VERSION 5.8 ;
BUSBITCHARS "[]" ;
DIVIDERCHAR "/" ;
UNITS
    DATABASE MICRONS 2000 ;
END UNITS

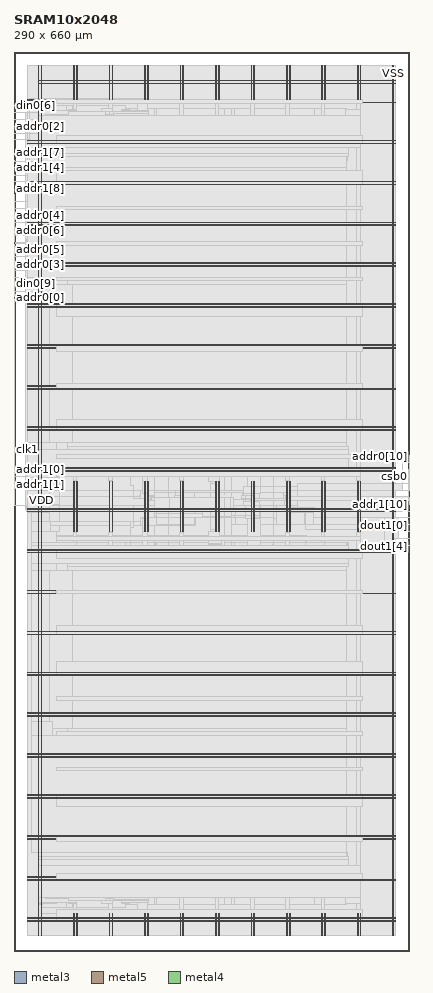
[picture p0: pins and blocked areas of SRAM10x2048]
MACRO SRAM10x2048
  FOREIGN SRAM10x2048 0 0 ;
  CLASS BLOCK ;
  SIZE 290 BY 660 ;
  PIN addr0[0]
    DIRECTION INPUT ;
    USE SIGNAL ;
    PORT
      LAYER metal3 ;
        RECT  0 478.835 0.07 478.905 ;
    END
  END addr0[0]
  PIN addr0[10]
    DIRECTION INPUT ;
    USE SIGNAL ;
    PORT
      LAYER metal3 ;
        RECT  289.93 362.915 290 362.985 ;
    END
  END addr0[10]
  PIN addr0[1]
    DIRECTION INPUT ;
    USE SIGNAL ;
    PORT
      LAYER metal3 ;
        RECT  0 609.875 0.07 609.945 ;
    END
  END addr0[1]
  PIN addr0[2]
    DIRECTION INPUT ;
    USE SIGNAL ;
    PORT
      LAYER metal3 ;
        RECT  0 604.835 0.07 604.905 ;
    END
  END addr0[2]
  PIN addr0[3]
    DIRECTION INPUT ;
    USE SIGNAL ;
    PORT
      LAYER metal3 ;
        RECT  0 509.075 0.07 509.145 ;
    END
  END addr0[3]
  PIN addr0[4]
    DIRECTION INPUT ;
    USE SIGNAL ;
    PORT
      LAYER metal3 ;
        RECT  0 539.315 0.07 539.385 ;
    END
  END addr0[4]
  PIN addr0[5]
    DIRECTION INPUT ;
    USE SIGNAL ;
    PORT
      LAYER metal3 ;
        RECT  0 514.115 0.07 514.185 ;
    END
  END addr0[5]
  PIN addr0[6]
    DIRECTION INPUT ;
    USE SIGNAL ;
    PORT
      LAYER metal3 ;
        RECT  0 534.275 0.07 534.345 ;
    END
  END addr0[6]
  PIN addr0[7]
    DIRECTION INPUT ;
    USE SIGNAL ;
    PORT
      LAYER metal3 ;
        RECT  0 519.155 0.07 519.225 ;
    END
  END addr0[7]
  PIN addr0[8]
    DIRECTION INPUT ;
    USE SIGNAL ;
    PORT
      LAYER metal3 ;
        RECT  0 529.235 0.07 529.305 ;
    END
  END addr0[8]
  PIN addr0[9]
    DIRECTION INPUT ;
    USE SIGNAL ;
    PORT
      LAYER metal3 ;
        RECT  0 524.195 0.07 524.265 ;
    END
  END addr0[9]
  PIN addr1[0]
    DIRECTION INPUT ;
    USE SIGNAL ;
    PORT
      LAYER metal3 ;
        RECT  0 352.835 0.07 352.905 ;
    END
  END addr1[0]
  PIN addr1[10]
    DIRECTION INPUT ;
    USE SIGNAL ;
    PORT
      LAYER metal3 ;
        RECT  289.93 327.635 290 327.705 ;
    END
  END addr1[10]
  PIN addr1[1]
    DIRECTION INPUT ;
    USE SIGNAL ;
    PORT
      LAYER metal3 ;
        RECT  0 347.795 0.07 347.865 ;
    END
  END addr1[1]
  PIN addr1[2]
    DIRECTION INPUT ;
    USE SIGNAL ;
    PORT
      LAYER metal3 ;
        RECT  0 342.755 0.07 342.825 ;
    END
  END addr1[2]
  PIN addr1[3]
    DIRECTION INPUT ;
    USE SIGNAL ;
    PORT
      LAYER metal3 ;
        RECT  0 549.395 0.07 549.465 ;
    END
  END addr1[3]
  PIN addr1[4]
    DIRECTION INPUT ;
    USE SIGNAL ;
    PORT
      LAYER metal3 ;
        RECT  0 574.595 0.07 574.665 ;
    END
  END addr1[4]
  PIN addr1[5]
    DIRECTION INPUT ;
    USE SIGNAL ;
    PORT
      LAYER metal3 ;
        RECT  0 569.555 0.07 569.625 ;
    END
  END addr1[5]
  PIN addr1[6]
    DIRECTION INPUT ;
    USE SIGNAL ;
    PORT
      LAYER metal3 ;
        RECT  0 564.515 0.07 564.585 ;
    END
  END addr1[6]
  PIN addr1[7]
    DIRECTION INPUT ;
    USE SIGNAL ;
    PORT
      LAYER metal3 ;
        RECT  0 579.635 0.07 579.705 ;
    END
  END addr1[7]
  PIN addr1[8]
    DIRECTION INPUT ;
    USE SIGNAL ;
    PORT
      LAYER metal3 ;
        RECT  0 559.475 0.07 559.545 ;
    END
  END addr1[8]
  PIN addr1[9]
    DIRECTION INPUT ;
    USE SIGNAL ;
    PORT
      LAYER metal3 ;
        RECT  0 584.675 0.07 584.745 ;
    END
  END addr1[9]
  PIN clk0
    DIRECTION INPUT ;
    USE SIGNAL ;
    PORT
      LAYER metal3 ;
        RECT  0 554.435 0.07 554.505 ;
    END
  END clk0
  PIN clk1
    DIRECTION INPUT ;
    USE SIGNAL ;
    PORT
      LAYER metal3 ;
        RECT  0 367.955 0.07 368.025 ;
    END
  END clk1
  PIN csb0
    DIRECTION INPUT ;
    USE SIGNAL ;
    PORT
      LAYER metal3 ;
        RECT  289.93 347.795 290 347.865 ;
    END
  END csb0
  PIN csb1
    DIRECTION INPUT ;
    USE SIGNAL ;
    PORT
      LAYER metal3 ;
        RECT  289.93 332.675 290 332.745 ;
    END
  END csb1
  PIN din0[0]
    DIRECTION INPUT ;
    USE SIGNAL ;
    PORT
      LAYER metal3 ;
        RECT  0 599.795 0.07 599.865 ;
    END
  END din0[0]
  PIN din0[1]
    DIRECTION INPUT ;
    USE SIGNAL ;
    PORT
      LAYER metal3 ;
        RECT  0 594.755 0.07 594.825 ;
    END
  END din0[1]
  PIN din0[2]
    DIRECTION INPUT ;
    USE SIGNAL ;
    PORT
      LAYER metal3 ;
        RECT  0 544.355 0.07 544.425 ;
    END
  END din0[2]
  PIN din0[3]
    DIRECTION INPUT ;
    USE SIGNAL ;
    PORT
      LAYER metal3 ;
        RECT  0 614.915 0.07 614.985 ;
    END
  END din0[3]
  PIN din0[4]
    DIRECTION INPUT ;
    USE SIGNAL ;
    PORT
      LAYER metal3 ;
        RECT  0 504.035 0.07 504.105 ;
    END
  END din0[4]
  PIN din0[5]
    DIRECTION INPUT ;
    USE SIGNAL ;
    PORT
      LAYER metal3 ;
        RECT  0 498.995 0.07 499.065 ;
    END
  END din0[5]
  PIN din0[6]
    DIRECTION INPUT ;
    USE SIGNAL ;
    PORT
      LAYER metal3 ;
        RECT  0 619.955 0.07 620.025 ;
    END
  END din0[6]
  PIN din0[7]
    DIRECTION INPUT ;
    USE SIGNAL ;
    PORT
      LAYER metal3 ;
        RECT  0 493.955 0.07 494.025 ;
    END
  END din0[7]
  PIN din0[8]
    DIRECTION INPUT ;
    USE SIGNAL ;
    PORT
      LAYER metal3 ;
        RECT  0 488.915 0.07 488.985 ;
    END
  END din0[8]
  PIN din0[9]
    DIRECTION INPUT ;
    USE SIGNAL ;
    PORT
      LAYER metal3 ;
        RECT  0 483.875 0.07 483.945 ;
    END
  END din0[9]
  PIN dout1[0]
    DIRECTION OUTPUT ;
    USE SIGNAL ;
    PORT
      LAYER metal3 ;
        RECT  289.93 317.555 290 317.625 ;
    END
  END dout1[0]
  PIN dout1[1]
    DIRECTION OUTPUT ;
    USE SIGNAL ;
    PORT
      LAYER metal3 ;
        RECT  289.93 312.515 290 312.585 ;
    END
  END dout1[1]
  PIN dout1[2]
    DIRECTION OUTPUT ;
    USE SIGNAL ;
    PORT
      LAYER metal3 ;
        RECT  289.93 357.875 290 357.945 ;
    END
  END dout1[2]
  PIN dout1[3]
    DIRECTION OUTPUT ;
    USE SIGNAL ;
    PORT
      LAYER metal3 ;
        RECT  289.93 337.715 290 337.785 ;
    END
  END dout1[3]
  PIN dout1[4]
    DIRECTION OUTPUT ;
    USE SIGNAL ;
    PORT
      LAYER metal3 ;
        RECT  289.93 302.435 290 302.505 ;
    END
  END dout1[4]
  PIN dout1[5]
    DIRECTION OUTPUT ;
    USE SIGNAL ;
    PORT
      LAYER metal3 ;
        RECT  289.93 352.835 290 352.905 ;
    END
  END dout1[5]
  PIN dout1[6]
    DIRECTION OUTPUT ;
    USE SIGNAL ;
    PORT
      LAYER metal3 ;
        RECT  289.93 297.395 290 297.465 ;
    END
  END dout1[6]
  PIN dout1[7]
    DIRECTION OUTPUT ;
    USE SIGNAL ;
    PORT
      LAYER metal3 ;
        RECT  289.93 342.755 290 342.825 ;
    END
  END dout1[7]
  PIN dout1[8]
    DIRECTION OUTPUT ;
    USE SIGNAL ;
    PORT
      LAYER metal3 ;
        RECT  289.93 307.475 290 307.545 ;
    END
  END dout1[8]
  PIN dout1[9]
    DIRECTION OUTPUT ;
    USE SIGNAL ;
    PORT
      LAYER metal3 ;
        RECT  289.93 322.595 290 322.665 ;
    END
  END dout1[9]
  PIN VSS
    DIRECTION INOUT ;
    USE GROUND ;
    PORT
      LAYER metal5 ;
        RECT  17.82 638.22 279.87 638.72 ;
        RECT  256.47 621.95 279.87 622.45 ;
        RECT  256.47 441.95 279.87 442.45 ;
        RECT  256.47 261.95 279.87 262.45 ;
        RECT  256.47 81.95 279.87 82.45 ;
        RECT  10.07 621.95 30.62 622.45 ;
        RECT  10.07 591.95 279.87 592.45 ;
        RECT  10.07 561.95 279.87 562.45 ;
        RECT  10.07 531.95 279.87 532.45 ;
        RECT  10.07 501.95 279.87 502.45 ;
        RECT  10.07 471.95 279.87 472.45 ;
        RECT  10.07 441.95 30.62 442.45 ;
        RECT  10.07 411.95 279.87 412.45 ;
        RECT  10.07 381.95 279.87 382.45 ;
        RECT  10.07 351.95 279.87 352.45 ;
        RECT  10.07 321.95 279.87 322.45 ;
        RECT  10.07 291.95 279.87 292.45 ;
        RECT  10.07 261.95 30.62 262.45 ;
        RECT  10.07 231.95 279.87 232.45 ;
        RECT  10.07 201.95 279.87 202.45 ;
        RECT  10.07 171.95 279.87 172.45 ;
        RECT  10.07 141.95 279.87 142.45 ;
        RECT  10.07 111.95 279.87 112.45 ;
        RECT  10.07 81.95 30.62 82.45 ;
        RECT  10.07 51.95 279.87 52.45 ;
        RECT  10.07 21.95 279.87 22.45 ;
      LAYER metal4 ;
        RECT  277.82 11.13 278.32 649.67 ;
        RECT  251.82 624.63 252.32 649.67 ;
        RECT  251.82 307.46 252.32 344.66 ;
        RECT  251.82 11.13 252.32 27.49 ;
        RECT  225.82 624.63 226.32 649.67 ;
        RECT  225.82 307.46 226.32 344.66 ;
        RECT  225.82 11.13 226.32 27.49 ;
        RECT  199.82 624.63 200.32 649.67 ;
        RECT  199.82 307.46 200.32 344.66 ;
        RECT  199.82 11.13 200.32 27.49 ;
        RECT  173.82 624.63 174.32 649.67 ;
        RECT  173.82 307.46 174.32 344.66 ;
        RECT  173.82 11.13 174.32 27.49 ;
        RECT  147.82 624.63 148.32 649.67 ;
        RECT  147.82 307.46 148.32 344.66 ;
        RECT  147.82 11.13 148.32 27.49 ;
        RECT  121.82 624.63 122.32 649.67 ;
        RECT  121.82 307.46 122.32 344.66 ;
        RECT  121.82 11.13 122.32 27.49 ;
        RECT  95.82 624.63 96.32 649.67 ;
        RECT  95.82 307.46 96.32 344.66 ;
        RECT  95.82 11.13 96.32 27.49 ;
        RECT  69.82 624.63 70.32 649.67 ;
        RECT  69.82 307.46 70.32 344.66 ;
        RECT  69.82 11.13 70.32 27.49 ;
        RECT  43.82 624.63 44.32 649.67 ;
        RECT  43.82 307.46 44.32 344.66 ;
        RECT  43.82 11.13 44.32 27.49 ;
        RECT  17.82 11.13 18.32 649.67 ;
    END
  END VSS
  PIN VDD
    DIRECTION INOUT ;
    USE POWER ;
    PORT
      LAYER metal5 ;
        RECT  17.82 635.98 279.87 636.48 ;
        RECT  10.07 624.05 30.62 624.55 ;
        RECT  10.07 594.05 279.87 594.55 ;
        RECT  10.07 564.05 279.87 564.55 ;
        RECT  10.07 534.05 279.87 534.55 ;
        RECT  10.07 504.05 279.87 504.55 ;
        RECT  10.07 474.05 279.87 474.55 ;
        RECT  10.07 444.05 279.87 444.55 ;
        RECT  10.07 414.05 30.62 414.55 ;
        RECT  10.07 384.05 279.87 384.55 ;
        RECT  10.07 354.05 279.87 354.55 ;
        RECT  10.07 324.05 279.87 324.55 ;
        RECT  10.07 294.05 279.87 294.55 ;
        RECT  10.07 264.05 30.62 264.55 ;
        RECT  10.07 234.05 279.87 234.55 ;
        RECT  10.07 204.05 279.87 204.55 ;
        RECT  10.07 174.05 279.87 174.55 ;
        RECT  10.07 144.05 279.87 144.55 ;
        RECT  10.07 114.05 279.87 114.55 ;
        RECT  10.07 84.05 279.87 84.55 ;
        RECT  10.07 54.05 30.62 54.55 ;
        RECT  10.07 24.05 279.87 24.55 ;
      LAYER metal4 ;
        RECT  253.92 624.42 254.42 649.64 ;
        RECT  253.92 307.49 254.42 344.63 ;
        RECT  253.92 11.16 254.42 27.7 ;
        RECT  227.92 624.42 228.42 649.64 ;
        RECT  227.92 307.49 228.42 344.63 ;
        RECT  227.92 11.16 228.42 27.7 ;
        RECT  201.92 624.42 202.42 649.64 ;
        RECT  201.92 307.49 202.42 344.63 ;
        RECT  201.92 11.16 202.42 27.7 ;
        RECT  175.92 624.42 176.42 649.64 ;
        RECT  175.92 307.49 176.42 344.63 ;
        RECT  175.92 11.16 176.42 27.7 ;
        RECT  149.92 624.42 150.42 649.64 ;
        RECT  149.92 307.49 150.42 344.63 ;
        RECT  149.92 11.16 150.42 27.7 ;
        RECT  123.92 624.42 124.42 649.64 ;
        RECT  123.92 307.49 124.42 344.63 ;
        RECT  123.92 11.16 124.42 27.7 ;
        RECT  97.92 624.42 98.42 649.64 ;
        RECT  97.92 307.49 98.42 344.63 ;
        RECT  97.92 11.16 98.42 27.7 ;
        RECT  71.92 624.42 72.42 649.64 ;
        RECT  71.92 307.49 72.42 344.63 ;
        RECT  71.92 11.16 72.42 27.7 ;
        RECT  45.92 624.42 46.42 649.64 ;
        RECT  45.92 307.49 46.42 344.63 ;
        RECT  45.92 11.16 46.42 27.7 ;
        RECT  19.92 11.16 20.42 649.64 ;
    END
  END VDD
  OBS
    LAYER metal1 ;
     RECT  10.07 11.115 279.87 649.685 ;
    LAYER metal2 ;
     RECT  17.84 11.13 18.3 12.53 ;
     RECT  43.84 11.13 44.3 12.53 ;
     RECT  69.84 11.13 70.3 12.53 ;
     RECT  95.84 11.13 96.3 12.53 ;
     RECT  121.84 11.13 122.3 12.53 ;
     RECT  147.84 11.13 148.3 12.53 ;
     RECT  173.84 11.13 174.3 12.53 ;
     RECT  199.84 11.13 200.3 12.53 ;
     RECT  225.84 11.13 226.3 12.53 ;
     RECT  251.84 11.13 252.3 12.53 ;
     RECT  43.84 12.53 46.4 26.67 ;
     RECT  69.84 12.53 72.4 26.67 ;
     RECT  95.84 12.53 98.4 26.67 ;
     RECT  121.84 12.53 124.4 26.67 ;
     RECT  147.84 12.53 150.4 26.67 ;
     RECT  173.84 12.53 176.4 26.67 ;
     RECT  199.84 12.53 202.4 26.67 ;
     RECT  225.84 12.53 228.4 26.67 ;
     RECT  251.84 12.53 254.4 26.67 ;
     RECT  43.84 26.67 45.99 28.21 ;
     RECT  69.84 26.67 71.99 28.21 ;
     RECT  95.84 26.67 97.99 28.21 ;
     RECT  121.84 26.67 123.99 28.21 ;
     RECT  147.84 26.67 149.99 28.21 ;
     RECT  173.84 26.67 175.99 28.21 ;
     RECT  199.84 26.67 201.99 28.21 ;
     RECT  225.84 26.67 227.99 28.21 ;
     RECT  251.84 26.67 253.99 28.21 ;
     RECT  244.4 35.42 244.47 36.96 ;
     RECT  43.43 28.21 45.99 39.28 ;
     RECT  69.43 28.21 71.99 39.28 ;
     RECT  95.43 28.21 97.99 39.28 ;
     RECT  121.43 28.21 123.99 39.28 ;
     RECT  147.43 28.21 149.99 39.28 ;
     RECT  173.43 28.21 175.99 39.28 ;
     RECT  199.43 28.21 201.99 39.28 ;
     RECT  225.43 28.21 227.99 39.28 ;
     RECT  244.21 36.96 244.47 39.28 ;
     RECT  43.385 39.28 244.47 60.13 ;
     RECT  17.84 12.53 20.4 62.58 ;
     RECT  17.84 62.58 22.93 68.6 ;
     RECT  43.385 60.13 244.28 72.1 ;
     RECT  43.385 72.1 244.05 297.49 ;
     RECT  43.43 297.49 45.99 305.55 ;
     RECT  69.43 297.49 71.99 305.55 ;
     RECT  95.43 297.49 97.99 305.55 ;
     RECT  121.43 297.49 123.99 305.55 ;
     RECT  173.43 297.49 175.99 305.55 ;
     RECT  199.43 297.49 201.99 305.55 ;
     RECT  225.43 297.49 227.99 305.55 ;
     RECT  251.43 28.21 253.99 305.55 ;
     RECT  147.43 297.49 149.99 307.72 ;
     RECT  284.87 307.44 284.94 309.26 ;
     RECT  43.84 305.55 45.99 309.33 ;
     RECT  69.84 305.55 71.99 309.33 ;
     RECT  95.84 305.55 97.99 309.33 ;
     RECT  121.84 305.55 123.99 309.33 ;
     RECT  144.08 307.72 149.99 309.33 ;
     RECT  173.84 305.55 175.99 309.33 ;
     RECT  199.84 305.55 201.99 309.33 ;
     RECT  225.84 305.55 227.99 309.33 ;
     RECT  251.84 305.55 253.99 309.33 ;
     RECT  159.47 297.49 159.54 312.48 ;
     RECT  103.04 297.49 103.11 315.14 ;
     RECT  95.84 309.33 98.4 316.82 ;
     RECT  173.84 309.33 176.4 316.82 ;
     RECT  192.72 315.14 192.79 316.82 ;
     RECT  92.78 316.82 98.4 318.08 ;
     RECT  121.84 309.33 124.4 318.08 ;
     RECT  190.25 316.82 192.79 318.08 ;
     RECT  33.5 307.86 33.57 318.22 ;
     RECT  121.84 318.08 124.58 318.22 ;
     RECT  103.04 315.14 104.44 318.5 ;
     RECT  132.68 312.34 132.75 318.5 ;
     RECT  199.84 309.33 202.4 318.5 ;
     RECT  33.12 318.5 33.19 318.64 ;
     RECT  190.25 318.08 192.41 318.64 ;
     RECT  132.49 318.5 132.94 318.78 ;
     RECT  190.25 318.64 191.84 318.92 ;
     RECT  103.04 318.5 104.63 320.88 ;
     RECT  190.25 318.92 191.08 320.88 ;
     RECT  214 309.12 214.07 320.88 ;
     RECT  219.7 320.74 219.77 321.16 ;
     RECT  212.86 321.16 213.69 321.3 ;
     RECT  10.7 321.3 11.72 321.335 ;
     RECT  213.05 321.3 213.69 321.44 ;
     RECT  213.05 321.44 213.12 321.72 ;
     RECT  138 320.74 138.07 322.28 ;
     RECT  159.47 312.48 162.2 322.28 ;
     RECT  9.75 321.335 11.72 322.56 ;
     RECT  218.94 321.16 219.77 322.56 ;
     RECT  159.47 322.28 161.82 322.7 ;
     RECT  159.47 322.7 161.25 323.54 ;
     RECT  191.01 320.88 191.08 323.68 ;
     RECT  199.84 318.5 205.33 323.68 ;
     RECT  154.34 301.98 154.41 323.82 ;
     RECT  9.56 322.56 12.67 324.1 ;
     RECT  158.9 323.54 161.25 324.1 ;
     RECT  8.61 324.1 13.62 324.24 ;
     RECT  87.65 310.52 87.72 324.24 ;
     RECT  157.76 324.1 161.25 324.38 ;
     RECT  218.94 322.56 220.15 325.08 ;
     RECT  8.61 324.24 12.67 325.5 ;
     RECT  218.94 325.08 219.77 325.5 ;
     RECT  8.61 325.5 11.72 325.64 ;
     RECT  198.42 323.68 205.33 326.34 ;
     RECT  17.84 68.6 20.4 326.48 ;
     RECT  169.73 316.82 169.8 326.48 ;
     RECT  17.84 326.48 21.98 326.62 ;
     RECT  17.84 326.62 21.22 327.04 ;
     RECT  17.84 327.04 20.65 327.32 ;
     RECT  103.04 320.88 104.25 329.28 ;
     RECT  173.84 316.82 180.06 329.7 ;
     RECT  289.81 327.6 289.88 330.82 ;
     RECT  95.84 318.08 98.4 330.96 ;
     RECT  167.83 329.14 167.9 330.96 ;
     RECT  121.84 318.22 124.4 331.1 ;
     RECT  167.07 330.96 167.9 331.1 ;
     RECT  173.34 329.7 180.06 331.1 ;
     RECT  104.18 329.28 104.25 331.24 ;
     RECT  198.42 326.34 207.61 331.52 ;
     RECT  118.05 331.1 124.4 331.94 ;
     RECT  198.42 331.52 207.99 331.94 ;
     RECT  137.81 322.56 137.88 332.08 ;
     RECT  167.07 331.1 180.06 332.08 ;
     RECT  197.66 331.94 207.99 332.08 ;
     RECT  95.84 330.96 99.5 332.22 ;
     RECT  157.95 324.38 161.25 332.22 ;
     RECT  159.47 332.22 161.25 332.64 ;
     RECT  92.78 332.22 99.5 332.78 ;
     RECT  92.21 332.78 99.5 333.2 ;
     RECT  33.12 333.76 33.19 333.9 ;
     RECT  92.21 333.2 103.3 333.9 ;
     RECT  117.86 331.94 124.4 333.9 ;
     RECT  167.07 332.08 169.8 333.9 ;
     RECT  197.66 332.08 202.4 333.9 ;
     RECT  118.43 333.9 124.4 334.18 ;
     RECT  92.78 333.9 98.4 335.3 ;
     RECT  113.3 316.82 113.37 335.3 ;
     RECT  167.26 333.9 169.8 335.3 ;
     RECT  173.84 332.08 180.06 335.3 ;
     RECT  190.25 325.36 190.32 335.3 ;
     RECT  103.04 333.9 103.3 336.42 ;
     RECT  167.26 335.3 167.33 336.42 ;
     RECT  132.49 318.78 132.56 336.56 ;
     RECT  154.34 335.04 154.6 336.56 ;
     RECT  197.85 333.9 202.4 336.56 ;
     RECT  289.43 333.48 289.5 337.54 ;
     RECT  118.43 334.18 124.58 337.68 ;
     RECT  118.43 337.68 124.4 337.96 ;
     RECT  173.84 335.3 179.49 337.96 ;
     RECT  87.65 332.08 87.72 341.6 ;
     RECT  207.92 332.08 207.99 342.86 ;
     RECT  43.84 309.33 46.4 343.07 ;
     RECT  69.84 309.33 72.4 343.07 ;
     RECT  95.84 335.3 98.4 343.07 ;
     RECT  121.84 337.96 124.4 343.07 ;
     RECT  144.08 309.33 150.4 343.07 ;
     RECT  173.84 337.96 176.4 343.07 ;
     RECT  199.84 336.56 202.4 343.07 ;
     RECT  225.84 309.33 228.4 343.07 ;
     RECT  251.84 309.33 254.4 343.07 ;
     RECT  144.08 343.07 149.99 344.4 ;
     RECT  43.84 343.07 45.99 346.57 ;
     RECT  69.84 343.07 71.99 346.57 ;
     RECT  95.84 343.07 97.99 346.57 ;
     RECT  121.84 343.07 123.99 346.57 ;
     RECT  173.84 343.07 175.99 346.57 ;
     RECT  199.84 343.07 201.99 346.57 ;
     RECT  225.84 343.07 227.99 346.57 ;
     RECT  251.84 343.07 253.99 346.57 ;
     RECT  33.5 334.18 33.57 347.62 ;
     RECT  154.34 336.56 154.41 350.14 ;
     RECT  289.43 337.54 289.88 352.94 ;
     RECT  43.43 346.57 45.99 354.63 ;
     RECT  69.43 346.57 71.99 354.63 ;
     RECT  95.43 346.57 97.99 354.63 ;
     RECT  103.04 336.42 103.11 354.63 ;
     RECT  121.43 346.57 123.99 354.63 ;
     RECT  147.43 344.4 149.99 354.63 ;
     RECT  159.47 332.64 159.54 354.63 ;
     RECT  173.43 346.57 175.99 354.63 ;
     RECT  199.43 346.57 201.99 354.63 ;
     RECT  225.43 346.57 227.99 354.63 ;
     RECT  284.87 340.48 284.94 357.98 ;
     RECT  289.81 352.94 289.88 363.02 ;
     RECT  17.84 327.32 20.4 481.46 ;
     RECT  17.84 481.46 21.22 488.74 ;
     RECT  8.61 325.64 11.34 527.1 ;
     RECT  8.61 527.1 11.53 529.06 ;
     RECT  8.61 529.06 11.34 537.32 ;
     RECT  8.61 537.32 11.53 539.28 ;
     RECT  17.84 488.74 20.4 578.48 ;
     RECT  43.385 354.63 244.05 580.02 ;
     RECT  17.84 578.48 21.22 584.08 ;
     RECT  17.84 584.08 21.41 588.84 ;
     RECT  43.385 580.02 244.28 591.99 ;
     RECT  8.61 539.28 11.34 603.12 ;
     RECT  8.61 603.12 11.53 604.66 ;
     RECT  8.61 604.66 11.34 612.64 ;
     RECT  43.385 591.99 244.47 612.84 ;
     RECT  10.13 612.64 11.53 614.88 ;
     RECT  10.13 614.88 11.34 615.02 ;
     RECT  244.21 612.84 244.47 615.16 ;
     RECT  10.13 615.02 11.15 616.7 ;
     RECT  244.4 615.16 244.47 616.7 ;
     RECT  10.51 616.7 11.15 617.26 ;
     RECT  10.7 617.26 11.15 621.18 ;
     RECT  10.13 621.18 11.15 622.3 ;
     RECT  10.51 622.3 11.15 622.86 ;
     RECT  10.7 622.86 11.15 623.84 ;
     RECT  43.43 612.84 45.99 623.91 ;
     RECT  69.43 612.84 71.99 623.91 ;
     RECT  95.43 612.84 97.99 623.91 ;
     RECT  121.43 612.84 123.99 623.91 ;
     RECT  147.43 612.84 149.99 623.91 ;
     RECT  173.43 612.84 175.99 623.91 ;
     RECT  199.43 612.84 201.99 623.91 ;
     RECT  225.43 612.84 227.99 623.91 ;
     RECT  251.43 346.57 253.99 623.91 ;
     RECT  11.08 623.84 11.15 624.96 ;
     RECT  43.84 623.91 45.99 625.73 ;
     RECT  69.84 623.91 71.99 625.73 ;
     RECT  95.84 623.91 97.99 625.73 ;
     RECT  121.84 623.91 123.99 625.73 ;
     RECT  147.84 623.91 149.99 625.73 ;
     RECT  173.84 623.91 175.99 625.73 ;
     RECT  199.84 623.91 201.99 625.73 ;
     RECT  225.84 623.91 227.99 625.73 ;
     RECT  251.84 623.91 253.99 625.73 ;
     RECT  17.84 588.84 20.4 648.27 ;
     RECT  43.84 625.73 46.4 648.27 ;
     RECT  69.84 625.73 72.4 648.27 ;
     RECT  95.84 625.73 98.4 648.27 ;
     RECT  121.84 625.73 124.4 648.27 ;
     RECT  147.84 625.73 150.4 648.27 ;
     RECT  173.84 625.73 176.4 648.27 ;
     RECT  199.84 625.73 202.4 648.27 ;
     RECT  225.84 625.73 228.4 648.27 ;
     RECT  251.84 625.73 254.4 648.27 ;
     RECT  17.84 648.27 18.3 649.67 ;
     RECT  43.84 648.27 44.3 649.67 ;
     RECT  69.84 648.27 70.3 649.67 ;
     RECT  95.84 648.27 96.3 649.67 ;
     RECT  121.84 648.27 122.3 649.67 ;
     RECT  147.84 648.27 148.3 649.67 ;
     RECT  173.84 648.27 174.3 649.67 ;
     RECT  199.84 648.27 200.3 649.67 ;
     RECT  225.84 648.27 226.3 649.67 ;
     RECT  251.84 648.27 252.3 649.67 ;
     RECT  277.84 11.13 278.3 649.67 ;
    LAYER metal3 ;
     RECT  0 489.055 0.035 489.825 ;
     RECT  0 559.615 0.035 559.825 ;
     RECT  0 568.575 0.035 569.485 ;
     RECT  0 579.215 0.035 579.565 ;
     RECT  0 584.255 0.035 584.605 ;
     RECT  0.035 524.195 0.06 524.265 ;
     RECT  0.035 488.915 0.13 489.825 ;
     RECT  0.06 524.195 0.13 524.405 ;
     RECT  0.035 559.475 0.13 559.825 ;
     RECT  0.035 568.575 0.13 569.625 ;
     RECT  0.035 579.215 0.13 579.705 ;
     RECT  0.035 584.255 0.13 584.745 ;
     RECT  0.025 554.435 0.165 554.505 ;
     RECT  0.025 326.935 8.575 327.005 ;
     RECT  0.035 609.875 8.575 609.945 ;
     RECT  0.035 614.915 8.575 614.985 ;
     RECT  0.035 604.835 8.765 604.905 ;
     RECT  0.035 529.235 8.955 529.305 ;
     RECT  0.035 514.115 9.335 514.185 ;
     RECT  9.335 514.115 9.475 516.145 ;
     RECT  8.575 324.135 9.525 327.005 ;
     RECT  0.035 519.155 9.525 519.225 ;
     RECT  8.955 529.235 9.525 530.005 ;
     RECT  0.035 534.275 9.525 534.345 ;
     RECT  0.13 489.755 9.86 489.825 ;
     RECT  9.86 489.755 9.93 490.665 ;
     RECT  0.035 544.355 10.045 544.425 ;
     RECT  0.035 539.315 10.095 539.385 ;
     RECT  0.035 619.955 10.095 620.025 ;
     RECT  9.525 322.595 10.105 327.005 ;
     RECT  9.93 490.595 10.235 490.665 ;
     RECT  0.035 493.955 10.235 494.025 ;
     RECT  0.035 509.075 10.235 509.145 ;
     RECT  9.475 515.795 10.235 516.145 ;
     RECT  9.525 519.155 10.235 521.465 ;
     RECT  0.13 524.335 10.235 524.405 ;
     RECT  9.525 529.235 10.235 534.345 ;
     RECT  8.765 604.835 10.235 607.005 ;
     RECT  10.095 619.955 10.245 621.285 ;
     RECT  0.035 549.395 10.285 549.465 ;
     RECT  0.035 599.795 10.425 599.865 ;
     RECT  0.035 504.035 10.475 504.105 ;
     RECT  10.235 532.175 10.475 534.345 ;
     RECT  10.095 539.315 10.475 541.065 ;
     RECT  10.475 552.615 10.51 552.685 ;
     RECT  10.235 516.075 10.615 516.145 ;
     RECT  10.51 552.475 10.615 552.685 ;
     RECT  10.475 504.035 10.77 504.805 ;
     RECT  10.475 532.175 10.77 541.065 ;
     RECT  0.035 478.835 10.805 478.905 ;
     RECT  0.035 483.875 10.805 483.945 ;
     RECT  0.035 498.995 10.805 499.065 ;
     RECT  10.77 532.595 10.805 541.065 ;
     RECT  10.77 504.035 10.995 504.665 ;
     RECT  10.615 552.475 10.995 552.545 ;
     RECT  10.995 504.035 11.045 504.525 ;
     RECT  10.805 534.135 11.045 541.065 ;
     RECT  10.285 547.855 11.045 549.465 ;
     RECT  8.575 609.875 11.045 614.985 ;
     RECT  11.045 501.655 11.185 504.525 ;
     RECT  10.475 526.995 11.185 529.025 ;
     RECT  11.045 534.135 11.185 542.045 ;
     RECT  10.475 602.595 11.185 604.625 ;
     RECT  11.045 609.735 11.185 614.985 ;
     RECT  0.13 579.215 11.225 579.285 ;
     RECT  10.105 321.335 11.375 327.005 ;
     RECT  0.035 594.755 11.375 594.825 ;
     RECT  11.185 614.775 11.375 614.985 ;
     RECT  11.375 322.595 11.755 327.005 ;
     RECT  11.755 322.735 12.705 327.005 ;
     RECT  0.035 574.595 12.765 574.665 ;
     RECT  12.705 324.135 13.655 327.005 ;
     RECT  0.035 352.835 14.215 352.905 ;
     RECT  14.215 352.835 14.285 353.045 ;
     RECT  17.105 333.375 17.42 333.445 ;
     RECT  12.625 72.555 17.84 72.625 ;
     RECT  13.655 326.935 17.84 327.005 ;
     RECT  17.42 333.375 17.84 333.585 ;
     RECT  0.035 342.755 17.84 342.825 ;
     RECT  0.035 347.795 17.84 347.865 ;
     RECT  14.285 352.975 17.84 353.045 ;
     RECT  0.035 367.955 17.84 368.025 ;
     RECT  11.045 481.775 17.84 481.845 ;
     RECT  11.045 485.975 17.84 486.045 ;
     RECT  11.045 491.575 17.84 491.645 ;
     RECT  11.045 497.175 17.84 497.245 ;
     RECT  11.185 501.655 17.84 501.725 ;
     RECT  11.045 508.935 17.84 509.005 ;
     RECT  11.045 512.855 17.84 512.925 ;
     RECT  11.045 519.015 17.84 519.085 ;
     RECT  11.045 524.055 17.84 524.125 ;
     RECT  11.185 528.955 17.84 529.025 ;
     RECT  11.185 534.135 17.84 534.205 ;
     RECT  11.185 539.175 17.84 542.045 ;
     RECT  11.045 547.575 17.84 549.465 ;
     RECT  0.13 559.755 17.84 559.825 ;
     RECT  0.035 564.515 17.84 564.585 ;
     RECT  0.13 568.575 17.84 568.645 ;
     RECT  11.225 579.075 17.84 579.285 ;
     RECT  0.13 584.255 17.84 584.325 ;
     RECT  11.045 599.655 17.84 599.725 ;
     RECT  11.185 604.555 17.84 604.625 ;
     RECT  11.185 609.735 17.84 609.805 ;
     RECT  11.375 614.775 17.84 614.845 ;
     RECT  10.245 620.375 17.84 620.445 ;
     RECT  11.045 624.855 17.84 624.925 ;
     RECT  17.84 11.13 18.3 649.67 ;
     RECT  18.3 12.53 20.4 648.27 ;
     RECT  20.4 342.755 20.885 342.825 ;
     RECT  20.4 57.435 21.16 58.345 ;
     RECT  20.4 512.855 21.16 514.045 ;
     RECT  20.4 528.955 21.16 529.165 ;
     RECT  20.4 539.175 21.16 544.285 ;
     RECT  20.4 604.555 21.16 604.765 ;
     RECT  20.4 614.775 21.16 620.445 ;
     RECT  20.4 97.755 21.165 98.665 ;
     RECT  20.4 294.315 21.165 295.085 ;
     RECT  20.4 351.855 21.165 353.045 ;
     RECT  20.4 357.035 21.165 357.805 ;
     RECT  20.4 547.295 21.165 549.465 ;
     RECT  20.4 553.455 21.165 554.365 ;
     RECT  21.165 97.755 21.255 97.825 ;
     RECT  20.4 481.495 21.255 493.885 ;
     RECT  21.165 554.295 21.255 554.365 ;
     RECT  20.4 497.175 21.445 503.965 ;
     RECT  20.4 588.735 21.445 589.645 ;
     RECT  20.4 87.675 21.535 87.885 ;
     RECT  20.4 564.375 21.535 569.485 ;
     RECT  20.4 153.195 21.725 153.405 ;
     RECT  21.445 497.175 21.725 498.925 ;
     RECT  20.4 82.635 21.815 82.845 ;
     RECT  21.535 564.515 21.815 569.485 ;
     RECT  20.4 158.235 22.005 158.445 ;
     RECT  21.255 487.235 22.005 493.885 ;
     RECT  20.4 77.595 22.095 77.805 ;
     RECT  20.4 574.455 22.095 574.525 ;
     RECT  20.4 299.355 22.285 299.565 ;
     RECT  20.4 347.655 22.285 347.865 ;
     RECT  21.165 351.855 22.285 352.765 ;
     RECT  20.4 72.555 22.375 72.625 ;
     RECT  20.4 578.515 22.375 579.565 ;
     RECT  20.4 138.075 22.565 138.285 ;
     RECT  21.16 513.135 22.565 514.045 ;
     RECT  20.4 67.515 22.655 68.565 ;
     RECT  20.4 584.115 22.655 584.605 ;
     RECT  20.4 143.115 22.845 143.465 ;
     RECT  20.4 508.235 22.845 509.005 ;
     RECT  20.4 62.475 22.935 62.685 ;
     RECT  21.445 589.575 22.935 589.645 ;
     RECT  22.935 62.615 22.965 62.685 ;
     RECT  20.4 47.355 23.215 47.425 ;
     RECT  21.16 604.695 23.215 604.765 ;
     RECT  22.655 68.355 23.405 68.565 ;
     RECT  22.375 578.515 23.405 578.585 ;
     RECT  22.095 77.735 23.685 77.805 ;
     RECT  21.815 564.515 23.685 568.645 ;
     RECT  21.815 82.775 23.965 82.845 ;
     RECT  23.685 564.515 23.965 564.585 ;
     RECT  23.685 568.575 23.965 568.645 ;
     RECT  21.535 87.815 24.245 87.885 ;
     RECT  20.4 558.495 24.245 559.405 ;
     RECT  20.4 148.155 24.525 148.365 ;
     RECT  21.165 547.295 24.525 549.325 ;
     RECT  23.405 68.495 24.805 68.565 ;
     RECT  22.655 584.115 24.805 584.185 ;
     RECT  20.4 163.275 25.925 165.445 ;
     RECT  22.005 487.235 25.925 488.845 ;
     RECT  20.4 168.315 26.205 168.525 ;
     RECT  21.255 481.495 26.205 483.805 ;
     RECT  20.4 311.955 26.905 312.445 ;
     RECT  20.4 284.235 27.045 284.445 ;
     RECT  26.205 168.315 28.255 168.385 ;
     RECT  26.205 483.735 28.255 483.805 ;
     RECT  20.4 337.575 29.705 337.785 ;
     RECT  20.4 367.675 29.845 367.885 ;
     RECT  20.4 102.795 31.055 102.865 ;
     RECT  24.525 549.255 31.055 549.325 ;
     RECT  22.285 347.655 31.385 347.725 ;
     RECT  20.4 279.055 31.525 279.265 ;
     RECT  20.4 372.715 31.525 372.925 ;
     RECT  20.4 52.395 32.595 52.465 ;
     RECT  20.4 599.655 32.595 599.725 ;
     RECT  20.4 42.315 32.735 42.385 ;
     RECT  21.16 57.435 32.735 57.505 ;
     RECT  20.4 594.615 32.735 594.685 ;
     RECT  20.4 609.735 32.735 609.805 ;
     RECT  20.4 333.375 33.085 333.445 ;
     RECT  33.085 318.535 33.485 318.605 ;
     RECT  20.4 326.515 33.485 327.285 ;
     RECT  33.085 333.375 33.485 333.865 ;
     RECT  31.385 307.895 33.605 307.965 ;
     RECT  31.385 347.515 33.605 347.725 ;
     RECT  22.005 158.235 33.855 158.305 ;
     RECT  22.005 493.815 33.855 493.885 ;
     RECT  22.285 299.355 36.515 299.425 ;
     RECT  22.285 352.695 36.515 352.765 ;
     RECT  24.525 148.155 36.655 148.225 ;
     RECT  27.045 284.235 36.655 284.305 ;
     RECT  29.845 367.815 36.655 367.885 ;
     RECT  21.445 503.895 36.655 503.965 ;
     RECT  22.565 138.075 36.935 138.145 ;
     RECT  22.565 513.975 36.935 514.045 ;
     RECT  36.515 299.355 38.195 299.565 ;
     RECT  36.515 352.555 38.195 352.765 ;
     RECT  20.4 32.235 38.335 37.345 ;
     RECT  21.165 294.315 38.335 294.385 ;
     RECT  21.165 357.735 38.335 357.805 ;
     RECT  21.16 614.775 38.335 619.885 ;
     RECT  38.195 299.355 39.315 299.705 ;
     RECT  38.195 352.415 39.315 352.765 ;
     RECT  25.925 163.275 39.455 163.345 ;
     RECT  31.525 279.195 39.455 279.265 ;
     RECT  31.525 372.855 39.455 372.925 ;
     RECT  25.925 488.775 39.455 488.845 ;
     RECT  21.725 153.195 39.735 153.265 ;
     RECT  21.725 498.855 39.735 498.925 ;
     RECT  22.845 143.115 40.015 143.185 ;
     RECT  22.845 508.935 40.015 509.005 ;
     RECT  20.4 107.835 40.155 107.905 ;
     RECT  21.16 544.215 40.155 544.285 ;
     RECT  32.595 52.395 40.295 54.285 ;
     RECT  20.4 133.035 40.295 133.105 ;
     RECT  20.4 519.015 40.295 519.085 ;
     RECT  32.595 597.835 40.295 599.725 ;
     RECT  20.4 112.875 40.995 112.945 ;
     RECT  21.16 539.175 40.995 539.245 ;
     RECT  20.4 117.915 41.275 117.985 ;
     RECT  20.4 534.135 41.275 534.205 ;
     RECT  40.295 54.215 42.395 54.285 ;
     RECT  40.295 597.835 42.395 597.905 ;
     RECT  40.155 107.835 42.71 109.865 ;
     RECT  40.995 112.875 42.71 114.765 ;
     RECT  40.995 537.355 42.71 539.245 ;
     RECT  40.155 542.255 42.71 544.285 ;
     RECT  38.335 32.235 43.245 36.925 ;
     RECT  42.395 54.215 43.245 55.405 ;
     RECT  36.795 104.755 43.245 104.825 ;
     RECT  42.71 107.835 43.245 114.765 ;
     RECT  41.275 117.915 43.245 119.665 ;
     RECT  39.315 299.215 43.245 299.705 ;
     RECT  39.315 352.415 43.245 352.905 ;
     RECT  41.275 532.455 43.245 534.205 ;
     RECT  42.71 537.355 43.245 544.285 ;
     RECT  36.795 547.295 43.245 547.365 ;
     RECT  42.395 596.715 43.245 597.905 ;
     RECT  38.335 615.195 43.245 619.885 ;
     RECT  43.245 32.235 43.385 39.84 ;
     RECT  43.245 54.18 43.385 55.405 ;
     RECT  20.4 92.715 43.385 92.785 ;
     RECT  43.245 104.75 43.385 119.71 ;
     RECT  20.4 122.955 43.385 123.025 ;
     RECT  20.4 127.995 43.385 128.065 ;
     RECT  43.245 296.93 43.385 299.705 ;
     RECT  43.245 352.415 43.385 355.19 ;
     RECT  20.4 524.055 43.385 524.125 ;
     RECT  21.16 529.095 43.385 529.165 ;
     RECT  43.245 532.41 43.385 547.37 ;
     RECT  24.245 559.335 43.385 559.405 ;
     RECT  43.245 596.715 43.385 597.94 ;
     RECT  43.245 612.28 43.385 619.885 ;
     RECT  20.4 27.195 43.43 27.265 ;
     RECT  43.385 32.235 43.43 299.705 ;
     RECT  20.4 304.395 43.43 304.465 ;
     RECT  33.605 347.655 43.43 347.725 ;
     RECT  43.385 352.415 43.43 619.885 ;
     RECT  20.4 624.855 43.43 624.925 ;
     RECT  33.485 333.375 43.46 333.445 ;
     RECT  43.43 27.195 43.84 305.55 ;
     RECT  26.905 311.955 43.84 315.245 ;
     RECT  33.485 326.515 43.84 326.585 ;
     RECT  43.46 333.375 43.84 333.585 ;
     RECT  29.705 337.575 43.84 337.925 ;
     RECT  43.43 346.57 43.84 624.925 ;
     RECT  43.84 11.13 44.3 649.67 ;
     RECT  44.3 12.53 45.99 648.27 ;
     RECT  45.99 12.53 46.4 27.265 ;
     RECT  45.99 309.33 46.4 343.07 ;
     RECT  45.99 624.855 46.4 648.27 ;
     RECT  46.4 27.195 69.43 27.265 ;
     RECT  45.99 32.235 69.43 299.705 ;
     RECT  45.99 304.395 69.43 304.465 ;
     RECT  45.99 347.655 69.43 347.725 ;
     RECT  45.99 352.415 69.43 619.885 ;
     RECT  46.4 624.855 69.43 624.925 ;
     RECT  46.4 333.375 69.5 333.445 ;
     RECT  69.43 27.195 69.84 305.55 ;
     RECT  46.4 311.955 69.84 315.245 ;
     RECT  46.4 326.515 69.84 326.585 ;
     RECT  69.5 333.375 69.84 333.585 ;
     RECT  46.4 337.575 69.84 337.925 ;
     RECT  69.43 346.57 69.84 624.925 ;
     RECT  69.84 11.13 70.3 649.67 ;
     RECT  70.3 12.53 71.99 648.27 ;
     RECT  71.99 12.53 72.4 27.265 ;
     RECT  71.99 309.33 72.4 343.07 ;
     RECT  71.99 624.855 72.4 648.27 ;
     RECT  72.4 333.235 74.135 333.445 ;
     RECT  71.99 32.235 81.735 299.705 ;
     RECT  71.99 352.415 81.735 619.885 ;
     RECT  72.4 311.955 85.235 315.245 ;
     RECT  72.4 326.515 87.615 326.585 ;
     RECT  74.135 333.375 87.615 333.445 ;
     RECT  85.235 310.555 87.755 315.245 ;
     RECT  85.235 341.495 87.755 341.565 ;
     RECT  72.4 27.195 90.415 27.265 ;
     RECT  72.4 624.855 90.415 624.925 ;
     RECT  87.755 311.955 92.745 315.245 ;
     RECT  87.615 332.115 92.745 333.445 ;
     RECT  72.4 337.575 92.745 337.925 ;
     RECT  81.735 34.055 95.43 299.705 ;
     RECT  71.99 304.395 95.43 304.465 ;
     RECT  71.99 347.655 95.43 347.725 ;
     RECT  81.735 352.415 95.43 618.065 ;
     RECT  95.43 28.21 95.84 305.55 ;
     RECT  92.745 311.955 95.84 318.045 ;
     RECT  87.615 324.135 95.84 326.585 ;
     RECT  92.745 332.115 95.84 337.925 ;
     RECT  95.43 346.57 95.84 623.91 ;
     RECT  95.84 28.21 95.89 623.91 ;
     RECT  95.84 11.13 96.3 25.27 ;
     RECT  95.84 627.13 96.3 649.67 ;
     RECT  96.3 12.53 97.94 25.27 ;
     RECT  96.3 627.13 97.94 648.27 ;
     RECT  95.89 29.61 97.99 622.51 ;
     RECT  97.94 12.53 98.4 26.67 ;
     RECT  97.99 309.33 98.4 343.07 ;
     RECT  97.94 625.73 98.4 648.27 ;
     RECT  98.4 330.575 100.105 333.585 ;
     RECT  100.105 330.575 100.485 333.305 ;
     RECT  97.99 34.055 103.005 299.705 ;
     RECT  98.4 324.135 103.005 326.585 ;
     RECT  100.485 330.575 103.005 332.325 ;
     RECT  97.99 352.415 103.005 618.065 ;
     RECT  98.4 337.575 103.195 337.925 ;
     RECT  103.005 34.055 104.135 299.845 ;
     RECT  103.005 352.275 104.135 618.065 ;
     RECT  98.4 311.955 104.475 318.045 ;
     RECT  104.475 317.975 104.525 318.045 ;
     RECT  104.525 317.975 113.235 320.845 ;
     RECT  103.195 336.315 113.235 337.925 ;
     RECT  113.235 316.855 113.405 320.845 ;
     RECT  113.235 335.195 113.405 337.925 ;
     RECT  103.005 324.135 113.965 332.325 ;
     RECT  113.405 336.315 118.535 337.925 ;
     RECT  104.135 34.055 121.43 299.705 ;
     RECT  97.99 304.395 121.43 304.465 ;
     RECT  97.99 347.655 121.43 347.725 ;
     RECT  104.135 352.415 121.43 618.065 ;
     RECT  121.43 28.21 121.84 305.55 ;
     RECT  104.475 311.955 121.84 312.445 ;
     RECT  113.405 317.975 121.84 320.845 ;
     RECT  113.965 324.135 121.84 332.605 ;
     RECT  118.535 336.315 121.84 337.785 ;
     RECT  121.43 346.57 121.84 623.91 ;
     RECT  121.84 28.21 121.89 623.91 ;
     RECT  121.84 11.13 122.3 25.27 ;
     RECT  121.84 627.13 122.3 649.67 ;
     RECT  122.3 12.53 123.94 25.27 ;
     RECT  122.3 627.13 123.94 648.27 ;
     RECT  121.89 29.61 123.99 622.51 ;
     RECT  123.94 12.53 124.4 26.67 ;
     RECT  123.99 309.33 124.4 343.07 ;
     RECT  123.94 625.73 124.4 648.27 ;
     RECT  124.4 312.375 132.785 312.445 ;
     RECT  124.4 317.975 138.105 320.845 ;
     RECT  138.105 317.975 144.045 318.745 ;
     RECT  142.915 307.755 144.185 307.825 ;
     RECT  142.915 344.295 144.185 344.365 ;
     RECT  123.99 34.055 147.43 299.705 ;
     RECT  123.99 304.395 147.43 304.465 ;
     RECT  123.99 347.655 147.43 347.725 ;
     RECT  123.99 352.415 147.43 618.065 ;
     RECT  147.43 28.21 147.84 305.55 ;
     RECT  144.045 317.975 147.84 318.885 ;
     RECT  124.4 324.135 147.84 332.605 ;
     RECT  124.4 336.315 147.84 337.785 ;
     RECT  147.43 346.57 147.84 623.91 ;
     RECT  147.84 28.21 147.89 623.91 ;
     RECT  147.84 11.13 148.3 25.27 ;
     RECT  147.84 627.13 148.3 649.67 ;
     RECT  148.3 12.53 149.94 25.27 ;
     RECT  148.3 627.13 149.94 648.27 ;
     RECT  147.89 29.61 149.99 622.51 ;
     RECT  149.94 12.53 150.4 26.67 ;
     RECT  149.99 309.33 150.4 343.07 ;
     RECT  149.94 625.73 150.4 648.27 ;
     RECT  150.4 324.135 154.305 332.605 ;
     RECT  149.99 34.055 154.445 304.465 ;
     RECT  149.99 347.655 154.445 618.065 ;
     RECT  154.305 323.715 158.865 332.605 ;
     RECT  154.445 34.055 159.435 299.705 ;
     RECT  150.4 317.975 159.435 318.885 ;
     RECT  154.445 352.415 159.435 618.065 ;
     RECT  158.865 323.575 161.095 332.605 ;
     RECT  161.095 326.795 161.285 332.605 ;
     RECT  159.435 34.055 161.815 299.845 ;
     RECT  159.435 352.275 161.815 618.065 ;
     RECT  159.435 317.975 161.855 319.025 ;
     RECT  161.285 326.795 167.935 331.065 ;
     RECT  150.4 336.315 168.175 337.645 ;
     RECT  168.175 334.355 168.445 337.645 ;
     RECT  161.855 318.255 169.695 319.025 ;
     RECT  161.095 323.575 169.695 323.785 ;
     RECT  167.935 326.795 169.695 326.865 ;
     RECT  167.935 329.735 169.695 331.065 ;
     RECT  169.695 329.735 173.305 331.205 ;
     RECT  161.815 34.055 173.43 299.705 ;
     RECT  154.445 304.395 173.43 304.465 ;
     RECT  154.445 347.655 173.43 347.725 ;
     RECT  161.815 352.415 173.43 618.065 ;
     RECT  173.43 28.21 173.84 305.55 ;
     RECT  162.095 312.515 173.84 312.585 ;
     RECT  169.695 316.855 173.84 319.025 ;
     RECT  169.695 323.575 173.84 326.865 ;
     RECT  173.305 329.735 173.84 332.045 ;
     RECT  168.445 335.195 173.84 337.645 ;
     RECT  168.305 340.515 173.84 340.585 ;
     RECT  173.43 346.57 173.84 623.91 ;
     RECT  173.84 28.21 173.89 623.91 ;
     RECT  173.84 11.13 174.3 25.27 ;
     RECT  173.84 627.13 174.3 649.67 ;
     RECT  174.3 12.53 175.94 25.27 ;
     RECT  174.3 627.13 175.94 648.27 ;
     RECT  173.89 29.61 175.99 622.51 ;
     RECT  175.94 12.53 176.4 26.67 ;
     RECT  175.99 309.33 176.4 343.07 ;
     RECT  175.94 625.73 176.4 648.27 ;
     RECT  176.4 318.255 179.955 319.025 ;
     RECT  176.4 323.575 179.955 326.445 ;
     RECT  176.4 336.455 179.955 340.585 ;
     RECT  179.955 316.855 180.575 326.445 ;
     RECT  179.955 335.195 180.575 340.585 ;
     RECT  180.575 318.255 189.955 326.445 ;
     RECT  180.575 336.455 189.955 340.585 ;
     RECT  189.955 335.195 190.355 340.585 ;
     RECT  176.4 312.515 192.685 312.585 ;
     RECT  189.955 316.855 192.685 326.445 ;
     RECT  176.4 330.715 198.765 332.045 ;
     RECT  175.99 34.055 199.43 299.705 ;
     RECT  175.99 304.395 199.43 304.465 ;
     RECT  175.99 347.655 199.43 347.725 ;
     RECT  175.99 352.415 199.43 618.065 ;
     RECT  199.43 28.21 199.84 305.55 ;
     RECT  192.685 312.515 199.84 326.445 ;
     RECT  198.765 330.715 199.84 333.585 ;
     RECT  190.355 336.455 199.84 340.585 ;
     RECT  199.43 346.57 199.84 623.91 ;
     RECT  199.84 28.21 199.89 623.91 ;
     RECT  199.84 11.13 200.3 25.27 ;
     RECT  199.84 627.13 200.3 649.67 ;
     RECT  200.3 12.53 201.94 25.27 ;
     RECT  200.3 627.13 201.94 648.27 ;
     RECT  199.89 29.61 201.99 622.51 ;
     RECT  201.94 12.53 202.4 26.67 ;
     RECT  201.99 309.33 202.4 343.07 ;
     RECT  201.94 625.73 202.4 648.27 ;
     RECT  202.4 325.395 207.645 326.445 ;
     RECT  202.4 337.575 207.885 340.585 ;
     RECT  202.4 312.515 213.155 321.685 ;
     RECT  213.155 312.515 213.725 321.405 ;
     RECT  201.99 304.395 214.175 304.465 ;
     RECT  201.99 347.655 214.175 347.725 ;
     RECT  207.645 325.395 219.235 325.465 ;
     RECT  213.725 312.515 219.805 321.265 ;
     RECT  201.99 34.055 220.055 299.705 ;
     RECT  201.99 352.415 220.055 618.065 ;
     RECT  220.055 34.055 225.43 299.565 ;
     RECT  220.055 352.555 225.43 618.065 ;
     RECT  225.43 28.21 225.84 305.55 ;
     RECT  213.965 309.155 225.84 309.225 ;
     RECT  219.805 312.515 225.84 318.045 ;
     RECT  220.045 322.595 225.84 322.665 ;
     RECT  202.4 330.715 225.84 333.585 ;
     RECT  207.885 337.575 225.84 342.825 ;
     RECT  225.43 346.57 225.84 623.91 ;
     RECT  225.84 28.21 225.89 623.91 ;
     RECT  225.84 11.13 226.3 25.27 ;
     RECT  225.84 627.13 226.3 649.67 ;
     RECT  226.3 12.53 227.94 25.27 ;
     RECT  226.3 627.13 227.94 648.27 ;
     RECT  225.89 29.61 227.99 622.51 ;
     RECT  227.94 12.53 228.4 26.67 ;
     RECT  227.99 309.155 228.4 343.07 ;
     RECT  227.94 625.73 228.4 648.27 ;
     RECT  227.99 34.055 243.575 299.565 ;
     RECT  227.99 352.555 243.575 618.065 ;
     RECT  243.575 34.895 244.05 299.565 ;
     RECT  243.575 352.555 244.05 617.225 ;
     RECT  244.05 34.895 244.19 39.84 ;
     RECT  244.05 57.82 244.19 72.78 ;
     RECT  244.05 281.785 244.19 282.16 ;
     RECT  244.05 296.93 244.19 299.565 ;
     RECT  244.05 352.555 244.19 355.19 ;
     RECT  244.05 369.96 244.19 370.335 ;
     RECT  244.05 579.34 244.19 594.3 ;
     RECT  244.05 612.28 244.19 617.225 ;
     RECT  244.19 34.895 244.315 37.065 ;
     RECT  244.19 71.995 244.315 72.065 ;
     RECT  244.19 580.055 244.315 580.125 ;
     RECT  244.19 615.055 244.315 617.225 ;
     RECT  244.19 57.855 244.505 69.125 ;
     RECT  244.19 582.995 244.505 594.265 ;
     RECT  244.19 281.855 244.66 282.09 ;
     RECT  244.19 370.03 244.66 370.265 ;
     RECT  244.505 62.755 244.975 69.125 ;
     RECT  244.66 281.855 244.975 282.065 ;
     RECT  244.19 299.215 244.975 299.565 ;
     RECT  244.19 352.555 244.975 352.905 ;
     RECT  244.66 370.055 244.975 370.265 ;
     RECT  244.505 582.995 244.975 589.365 ;
     RECT  244.315 34.895 245.255 36.925 ;
     RECT  244.975 62.755 245.255 67.165 ;
     RECT  244.975 281.995 245.255 282.065 ;
     RECT  244.975 299.495 245.255 299.565 ;
     RECT  244.975 352.555 245.255 352.625 ;
     RECT  244.975 370.055 245.255 370.125 ;
     RECT  244.975 584.955 245.255 589.365 ;
     RECT  244.315 615.195 245.255 617.225 ;
     RECT  245.255 34.895 245.535 36.365 ;
     RECT  245.255 67.095 245.535 67.165 ;
     RECT  245.255 584.955 245.535 585.025 ;
     RECT  245.255 615.755 245.535 617.225 ;
     RECT  245.535 34.895 245.815 36.225 ;
     RECT  245.255 62.755 245.815 62.825 ;
     RECT  245.255 589.295 245.815 589.365 ;
     RECT  245.535 615.895 245.815 617.225 ;
     RECT  245.815 34.895 246.095 34.965 ;
     RECT  244.505 57.855 246.095 57.925 ;
     RECT  244.505 594.195 246.095 594.265 ;
     RECT  245.815 617.155 246.095 617.225 ;
     RECT  251.43 28.21 251.84 305.55 ;
     RECT  228.4 309.155 251.84 309.225 ;
     RECT  228.4 312.515 251.84 318.045 ;
     RECT  228.4 322.595 251.84 322.665 ;
     RECT  228.4 330.715 251.84 333.585 ;
     RECT  228.4 337.575 251.84 342.825 ;
     RECT  251.43 346.57 251.84 623.91 ;
     RECT  251.84 28.21 251.89 623.91 ;
     RECT  251.84 11.13 252.3 25.27 ;
     RECT  251.84 627.13 252.3 649.67 ;
     RECT  252.3 12.53 253.94 25.27 ;
     RECT  252.3 627.13 253.94 648.27 ;
     RECT  251.89 29.61 253.99 622.51 ;
     RECT  253.94 12.53 254.4 26.67 ;
     RECT  253.99 309.155 254.4 343.07 ;
     RECT  253.94 625.73 254.4 648.27 ;
     RECT  254.4 312.515 272.045 318.045 ;
     RECT  271.905 297.395 277.84 297.465 ;
     RECT  254.4 309.155 277.84 309.225 ;
     RECT  272.045 312.515 277.84 317.625 ;
     RECT  254.4 322.595 277.84 322.665 ;
     RECT  254.4 330.715 277.84 333.585 ;
     RECT  254.4 337.575 277.84 342.825 ;
     RECT  277.84 11.13 278.3 649.67 ;
     RECT  278.3 312.515 282.125 317.625 ;
     RECT  278.3 309.155 284.835 309.225 ;
     RECT  284.835 307.475 284.975 309.225 ;
     RECT  278.3 337.575 284.975 342.825 ;
     RECT  278.3 330.715 289.535 333.585 ;
     RECT  284.975 337.575 289.725 337.925 ;
     RECT  289.535 330.715 289.915 332.745 ;
     RECT  289.725 337.575 289.915 337.785 ;
     RECT  278.3 297.395 289.965 297.465 ;
     RECT  281.985 302.435 289.965 302.505 ;
     RECT  284.975 307.475 289.965 307.545 ;
     RECT  282.125 312.515 289.965 312.585 ;
     RECT  282.125 317.555 289.965 317.625 ;
     RECT  278.3 322.595 289.965 322.665 ;
     RECT  289.775 327.635 289.965 327.705 ;
     RECT  289.915 330.855 289.965 332.745 ;
     RECT  289.915 337.715 289.965 337.785 ;
     RECT  284.975 342.755 289.965 342.825 ;
     RECT  289.585 347.795 289.965 347.865 ;
     RECT  289.395 352.835 289.965 352.905 ;
     RECT  284.835 357.875 289.965 357.945 ;
     RECT  289.775 362.915 289.965 362.985 ;
     RECT  289.965 330.855 290 332.605 ;
    LAYER metal4 ;
     RECT  17.82 11.13 18.32 11.16 ;
     RECT  43.82 11.13 44.32 11.16 ;
     RECT  69.82 11.13 70.32 11.16 ;
     RECT  95.82 11.13 96.32 11.16 ;
     RECT  121.82 11.13 122.32 11.16 ;
     RECT  147.82 11.13 148.32 11.16 ;
     RECT  173.82 11.13 174.32 11.16 ;
     RECT  199.82 11.13 200.32 11.16 ;
     RECT  225.82 11.13 226.32 11.16 ;
     RECT  251.82 11.13 252.32 11.16 ;
     RECT  95.82 11.16 98.42 27.16 ;
     RECT  43.82 11.16 46.42 27.7 ;
     RECT  69.82 11.16 72.42 27.7 ;
     RECT  90.275 27.16 98.42 27.7 ;
     RECT  121.82 11.16 124.42 27.7 ;
     RECT  147.82 11.16 150.42 27.7 ;
     RECT  173.82 11.16 176.42 27.7 ;
     RECT  199.82 11.16 202.42 27.7 ;
     RECT  225.82 11.16 228.42 27.7 ;
     RECT  251.82 11.16 254.42 27.7 ;
     RECT  43.82 27.7 46.01 28.03 ;
     RECT  69.82 27.7 72.01 28.03 ;
     RECT  121.82 27.7 124.01 28.03 ;
     RECT  147.82 27.7 150.01 28.03 ;
     RECT  173.82 27.7 176.01 28.03 ;
     RECT  199.82 27.7 202.01 28.03 ;
     RECT  225.82 27.7 228.01 28.03 ;
     RECT  251.82 27.7 254.01 28.03 ;
     RECT  17.82 11.16 20.42 34.02 ;
     RECT  69.41 28.03 72.01 34.58 ;
     RECT  43.41 28.03 46.01 34.72 ;
     RECT  81.595 32.2 81.735 34.72 ;
     RECT  17.82 34.02 21.255 34.86 ;
     RECT  28.115 34.58 28.255 34.86 ;
     RECT  243.435 34.02 243.575 34.86 ;
     RECT  251.41 28.03 254.01 34.86 ;
     RECT  17.82 34.86 28.255 35 ;
     RECT  81.595 34.72 84.535 35 ;
     RECT  17.82 35 31.055 35.56 ;
     RECT  39.875 34.72 46.01 35.56 ;
     RECT  78.795 35 84.535 35.56 ;
     RECT  90.275 27.7 98.01 35.56 ;
     RECT  78.795 35.56 98.01 35.84 ;
     RECT  64.515 34.58 72.01 36.68 ;
     RECT  78.795 35.84 98.815 36.68 ;
     RECT  64.515 36.68 98.815 37.8 ;
     RECT  17.82 35.56 46.01 39.28 ;
     RECT  64.515 37.8 98.975 39.28 ;
     RECT  121.41 28.03 124.01 39.28 ;
     RECT  147.41 28.03 150.01 39.28 ;
     RECT  173.41 28.03 176.01 39.28 ;
     RECT  199.41 28.03 202.01 39.28 ;
     RECT  225.41 28.03 228.01 39.28 ;
     RECT  243.435 34.86 254.01 39.28 ;
     RECT  17.82 39.28 254.01 62.86 ;
     RECT  17.82 62.86 245.535 67.2 ;
     RECT  17.82 67.2 244.975 69.16 ;
     RECT  17.82 69.16 244.19 72.52 ;
     RECT  12.625 72.52 244.19 158.34 ;
     RECT  39.315 158.34 244.19 163.38 ;
     RECT  12.625 158.34 28.255 168.42 ;
     RECT  12.625 168.42 26.205 279.02 ;
     RECT  43.245 163.38 244.19 279.16 ;
     RECT  39.315 279.16 244.19 281.82 ;
     RECT  39.315 281.82 244.975 281.96 ;
     RECT  12.625 279.02 31.525 284.2 ;
     RECT  39.315 281.96 245.255 284.2 ;
     RECT  12.625 284.2 245.255 297.49 ;
     RECT  243.49 297.49 245.255 297.63 ;
     RECT  103.975 297.49 104.135 298.06 ;
     RECT  113.235 297.49 113.515 298.06 ;
     RECT  142.835 297.49 152.375 298.06 ;
     RECT  161.635 297.49 161.815 298.06 ;
     RECT  189.835 297.49 190.095 298.06 ;
     RECT  85.175 297.49 85.375 298.9 ;
     RECT  142.915 298.06 152.375 298.9 ;
     RECT  244.835 297.63 245.255 299.32 ;
     RECT  214.035 297.49 228.01 299.46 ;
     RECT  12.625 297.49 46.01 299.6 ;
     RECT  245.115 299.32 245.255 299.6 ;
     RECT  38.195 299.6 46.01 299.74 ;
     RECT  219.915 299.46 228.01 299.74 ;
     RECT  103.995 298.06 104.135 299.88 ;
     RECT  161.675 298.06 161.815 299.88 ;
     RECT  142.915 298.9 152.295 302.12 ;
     RECT  277.82 11.13 278.32 302.4 ;
     RECT  214.035 299.46 214.175 304.5 ;
     RECT  43.41 299.74 46.01 306.92 ;
     RECT  69.41 297.49 72.01 306.92 ;
     RECT  121.41 297.49 124.01 306.92 ;
     RECT  199.41 297.49 202.01 306.92 ;
     RECT  225.41 299.74 228.01 306.92 ;
     RECT  251.41 62.86 254.01 306.92 ;
     RECT  43.82 306.92 46.01 307.49 ;
     RECT  69.82 306.92 72.01 307.49 ;
     RECT  94.475 297.49 98.01 307.49 ;
     RECT  121.82 306.92 124.01 307.49 ;
     RECT  199.82 306.92 202.01 307.49 ;
     RECT  225.82 306.92 228.01 307.49 ;
     RECT  251.82 306.92 254.01 307.49 ;
     RECT  142.915 302.12 150.42 307.86 ;
     RECT  12.625 299.6 31.525 308 ;
     RECT  85.235 298.9 85.375 310.66 ;
     RECT  12.625 308 27.045 315.28 ;
     RECT  277.82 302.4 282.125 315.28 ;
     RECT  94.475 307.49 98.42 316.96 ;
     RECT  113.235 298.06 113.375 316.96 ;
     RECT  170.915 297.49 180.575 316.96 ;
     RECT  189.955 298.06 190.095 316.96 ;
     RECT  271.905 297.36 272.045 318.08 ;
     RECT  12.625 315.28 26.205 321.3 ;
     RECT  33.345 318.5 33.485 333.9 ;
     RECT  173.82 316.96 176.42 334.32 ;
     RECT  95.82 316.96 98.42 335.16 ;
     RECT  168.305 334.32 176.42 335.16 ;
     RECT  10.105 321.3 26.205 337.82 ;
     RECT  168.305 335.16 180.575 340.62 ;
     RECT  147.82 307.86 150.42 344.26 ;
     RECT  43.82 307.49 46.42 344.63 ;
     RECT  69.82 307.49 72.42 344.63 ;
     RECT  94.475 335.16 98.42 344.63 ;
     RECT  121.82 307.49 124.42 344.63 ;
     RECT  199.82 307.49 202.42 344.63 ;
     RECT  225.82 307.49 228.42 344.63 ;
     RECT  251.82 307.49 254.42 344.63 ;
     RECT  43.82 344.63 46.01 345.2 ;
     RECT  69.82 344.63 72.01 345.2 ;
     RECT  121.82 344.63 124.01 345.2 ;
     RECT  199.82 344.63 202.01 345.2 ;
     RECT  225.82 344.63 228.01 345.2 ;
     RECT  251.82 344.63 254.01 345.2 ;
     RECT  10.105 337.82 29.845 347.48 ;
     RECT  142.915 344.26 150.42 350 ;
     RECT  43.41 345.2 46.01 352.38 ;
     RECT  225.41 345.2 228.01 352.38 ;
     RECT  10.105 347.48 31.525 352.52 ;
     RECT  38.195 352.38 46.01 352.52 ;
     RECT  214.035 347.62 214.175 352.66 ;
     RECT  219.915 352.38 228.01 352.66 ;
     RECT  245.115 352.52 245.255 352.8 ;
     RECT  85.235 341.46 85.375 353.22 ;
     RECT  142.915 350 152.295 353.22 ;
     RECT  103.995 352.24 104.135 354.06 ;
     RECT  113.235 335.16 113.375 354.06 ;
     RECT  142.915 353.22 152.375 354.06 ;
     RECT  161.675 352.24 161.815 354.06 ;
     RECT  189.955 335.16 190.095 354.06 ;
     RECT  244.835 352.8 245.255 354.49 ;
     RECT  10.105 352.52 46.01 354.63 ;
     RECT  69.41 345.2 72.01 354.63 ;
     RECT  85.175 353.22 85.375 354.63 ;
     RECT  94.475 344.63 98.01 354.63 ;
     RECT  103.975 354.06 104.135 354.63 ;
     RECT  113.235 354.06 113.515 354.63 ;
     RECT  121.41 345.2 124.01 354.63 ;
     RECT  142.835 354.06 152.375 354.63 ;
     RECT  161.635 354.06 161.815 354.63 ;
     RECT  170.915 340.62 180.575 354.63 ;
     RECT  189.835 354.06 190.095 354.63 ;
     RECT  199.41 345.2 202.01 354.63 ;
     RECT  214.035 352.66 228.01 354.63 ;
     RECT  243.49 354.49 245.255 354.63 ;
     RECT  10.105 354.63 245.255 367.92 ;
     RECT  39.315 367.92 245.255 370.16 ;
     RECT  39.315 370.16 244.975 370.3 ;
     RECT  10.105 367.92 31.525 372.82 ;
     RECT  39.315 370.3 244.19 372.96 ;
     RECT  10.105 372.82 26.205 483.7 ;
     RECT  43.245 372.96 244.19 488.74 ;
     RECT  10.105 483.7 28.255 493.78 ;
     RECT  39.315 488.74 244.19 493.78 ;
     RECT  0.025 326.9 0.165 554.54 ;
     RECT  10.105 493.78 244.19 574.7 ;
     RECT  10.105 574.7 11.365 579.18 ;
     RECT  17.82 574.7 244.19 582.96 ;
     RECT  17.82 582.96 244.975 584.92 ;
     RECT  17.82 584.92 245.535 589.26 ;
     RECT  251.41 345.2 254.01 589.26 ;
     RECT  17.82 589.26 254.01 612.84 ;
     RECT  64.515 612.84 98.975 614.32 ;
     RECT  64.515 614.32 98.815 615.44 ;
     RECT  78.795 615.44 98.815 616.28 ;
     RECT  17.82 612.84 46.01 616.56 ;
     RECT  78.795 616.28 98.01 616.56 ;
     RECT  17.82 616.56 31.055 617.12 ;
     RECT  78.795 616.56 84.535 617.12 ;
     RECT  17.82 617.12 28.255 617.26 ;
     RECT  243.435 612.84 254.01 617.26 ;
     RECT  39.875 616.56 46.01 617.4 ;
     RECT  81.595 617.12 84.535 617.4 ;
     RECT  28.115 617.26 28.255 617.54 ;
     RECT  64.515 615.44 72.01 617.54 ;
     RECT  17.82 617.26 21.255 618.1 ;
     RECT  243.435 617.26 243.575 618.1 ;
     RECT  81.595 617.4 81.735 619.92 ;
     RECT  10.105 579.18 10.245 621.32 ;
     RECT  43.41 617.4 46.01 624.09 ;
     RECT  69.41 617.54 72.01 624.09 ;
     RECT  121.41 612.84 124.01 624.09 ;
     RECT  147.41 612.84 150.01 624.09 ;
     RECT  173.41 612.84 176.01 624.09 ;
     RECT  199.41 612.84 202.01 624.09 ;
     RECT  225.41 612.84 228.01 624.09 ;
     RECT  251.41 617.26 254.01 624.09 ;
     RECT  43.82 624.09 46.01 624.42 ;
     RECT  69.82 624.09 72.01 624.42 ;
     RECT  90.275 616.56 98.01 624.42 ;
     RECT  121.82 624.09 124.01 624.42 ;
     RECT  147.82 624.09 150.01 624.42 ;
     RECT  173.82 624.09 176.01 624.42 ;
     RECT  199.82 624.09 202.01 624.42 ;
     RECT  225.82 624.09 228.01 624.42 ;
     RECT  251.82 624.09 254.01 624.42 ;
     RECT  90.275 624.42 98.42 624.96 ;
     RECT  17.82 618.1 20.42 649.64 ;
     RECT  43.82 624.42 46.42 649.64 ;
     RECT  69.82 624.42 72.42 649.64 ;
     RECT  95.82 624.96 98.42 649.64 ;
     RECT  121.82 624.42 124.42 649.64 ;
     RECT  147.82 624.42 150.42 649.64 ;
     RECT  173.82 624.42 176.42 649.64 ;
     RECT  199.82 624.42 202.42 649.64 ;
     RECT  225.82 624.42 228.42 649.64 ;
     RECT  251.82 624.42 254.42 649.64 ;
     RECT  17.82 649.64 18.32 649.67 ;
     RECT  43.82 649.64 44.32 649.67 ;
     RECT  69.82 649.64 70.32 649.67 ;
     RECT  95.82 649.64 96.32 649.67 ;
     RECT  121.82 649.64 122.32 649.67 ;
     RECT  147.82 649.64 148.32 649.67 ;
     RECT  173.82 649.64 174.32 649.67 ;
     RECT  199.82 649.64 200.32 649.67 ;
     RECT  225.82 649.64 226.32 649.67 ;
     RECT  251.82 649.64 252.32 649.67 ;
     RECT  277.82 315.28 278.32 649.67 ;
    LAYER metal5 ;
     RECT  10.07 261.95 30.62 264.55 ;
     RECT  10.07 621.95 30.62 624.55 ;
     RECT  10.07 21.95 31.16 24.55 ;
     RECT  10.07 51.95 31.16 54.55 ;
     RECT  10.07 81.95 31.16 84.55 ;
     RECT  10.07 111.95 31.16 114.55 ;
     RECT  10.07 201.95 31.16 204.55 ;
     RECT  10.07 231.95 31.16 234.55 ;
     RECT  30.62 262.03 31.16 264.55 ;
     RECT  10.07 291.95 31.16 294.55 ;
     RECT  10.07 351.95 31.16 354.55 ;
     RECT  10.07 381.95 31.16 384.55 ;
     RECT  10.07 411.95 31.16 414.55 ;
     RECT  10.07 441.95 31.16 444.55 ;
     RECT  10.07 471.95 31.16 474.55 ;
     RECT  10.07 561.95 31.16 564.55 ;
     RECT  10.07 591.95 31.16 594.55 ;
     RECT  30.62 621.95 31.16 624.09 ;
     RECT  23.075 38.36 32.595 38.5 ;
     RECT  23.075 613.62 32.595 613.76 ;
     RECT  32.595 38.36 38.195 38.78 ;
     RECT  32.595 613.34 38.195 613.76 ;
     RECT  38.195 38.36 40.155 39.06 ;
     RECT  38.195 613.06 40.155 613.76 ;
     RECT  40.155 36.68 67.315 39.06 ;
     RECT  40.155 613.06 67.315 615.44 ;
     RECT  67.315 36.68 67.455 39.28 ;
     RECT  67.315 612.84 67.455 615.44 ;
     RECT  67.455 36.68 70.375 38.78 ;
     RECT  67.455 613.34 70.375 615.44 ;
     RECT  70.375 36.68 73.235 38.5 ;
     RECT  70.375 613.62 73.235 615.44 ;
     RECT  73.235 36.68 76.135 36.82 ;
     RECT  73.235 615.3 76.135 615.44 ;
     RECT  31.16 301.1 254.01 303.84 ;
     RECT  31.16 348.28 254.01 354.55 ;
     RECT  31.16 21.95 255.93 30.63 ;
     RECT  31.16 51.95 255.93 56.63 ;
     RECT  31.16 80.03 255.93 84.55 ;
     RECT  31.16 106.03 255.93 114.55 ;
     RECT  31.16 132.03 255.93 134.63 ;
     RECT  31.16 158.03 255.93 160.63 ;
     RECT  31.16 184.03 255.93 186.63 ;
     RECT  31.16 201.95 255.93 212.63 ;
     RECT  31.16 231.95 255.93 238.63 ;
     RECT  31.16 262.03 255.93 264.63 ;
     RECT  31.16 288.03 255.93 294.55 ;
     RECT  31.16 361.49 255.93 364.09 ;
     RECT  31.16 381.95 255.93 390.09 ;
     RECT  31.16 411.95 255.93 416.09 ;
     RECT  31.16 439.49 255.93 444.55 ;
     RECT  31.16 465.49 255.93 474.55 ;
     RECT  31.16 491.49 255.93 494.09 ;
     RECT  31.16 517.49 255.93 520.09 ;
     RECT  31.16 543.49 255.93 546.09 ;
     RECT  31.16 561.95 255.93 572.09 ;
     RECT  31.16 591.95 255.93 598.09 ;
     RECT  31.16 621.49 255.93 624.09 ;
     RECT  255.93 262.03 256.47 262.45 ;
     RECT  255.93 21.95 279.87 24.55 ;
     RECT  255.93 51.95 279.87 52.45 ;
     RECT  255.93 81.95 279.87 84.55 ;
     RECT  255.93 111.95 279.87 114.55 ;
     RECT  10.07 141.95 279.87 144.55 ;
     RECT  10.07 171.95 279.87 174.55 ;
     RECT  255.93 201.95 279.87 204.55 ;
     RECT  255.93 231.95 279.87 234.55 ;
     RECT  256.47 261.95 279.87 262.45 ;
     RECT  255.93 291.95 279.87 294.55 ;
     RECT  10.07 321.95 279.87 324.55 ;
     RECT  254.01 351.95 279.87 354.55 ;
     RECT  255.93 381.95 279.87 384.55 ;
     RECT  255.93 411.95 279.87 412.45 ;
     RECT  255.93 441.95 279.87 444.55 ;
     RECT  255.93 471.95 279.87 474.55 ;
     RECT  10.07 501.95 279.87 504.55 ;
     RECT  10.07 531.95 279.87 534.55 ;
     RECT  255.93 561.95 279.87 564.55 ;
     RECT  255.93 591.95 279.87 594.55 ;
     RECT  255.93 621.95 279.87 622.45 ;
     RECT  17.82 635.98 279.87 638.72 ;
  END
END SRAM10x2048
END LIBRARY
